VERSION 5.7 ;
BUSBITCHARS "[]" ;
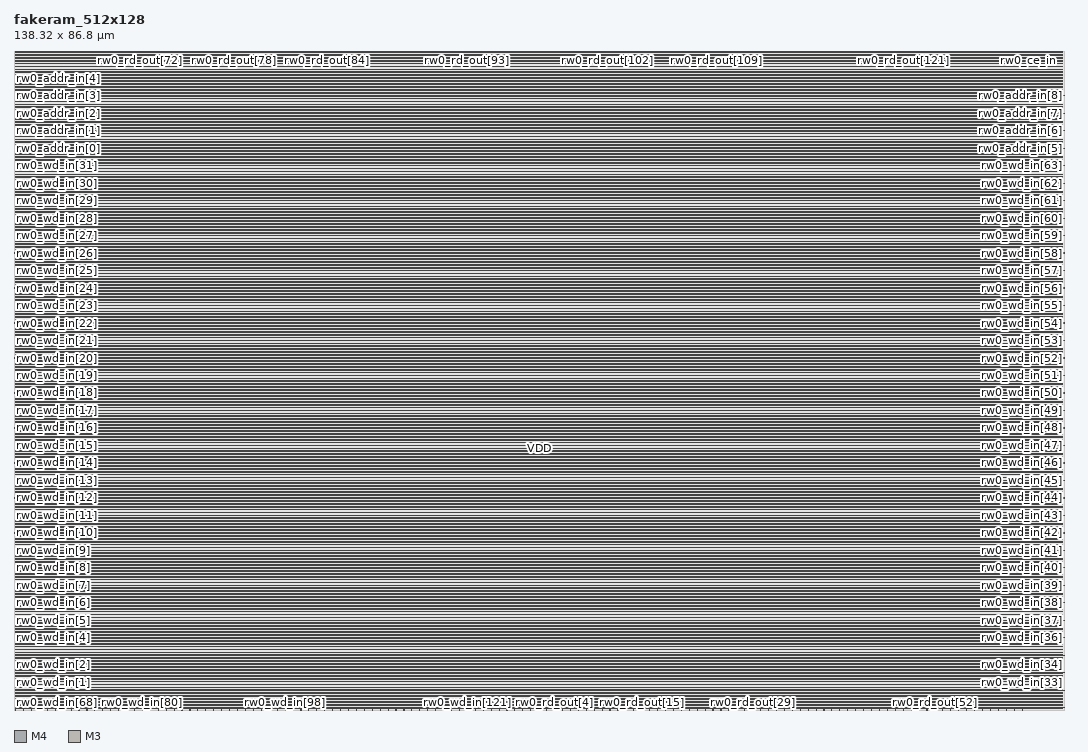
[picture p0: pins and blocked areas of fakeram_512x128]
MACRO fakeram_512x128
  FOREIGN fakeram_512x128 0 0 ;
  SYMMETRY X Y R90 ;
  SIZE 138.320 BY 86.800 ;
  CLASS BLOCK ;
  PIN rw0_wd_in[0]
    DIRECTION INPUT ;
    USE SIGNAL ;
    SHAPE ABUTMENT ;
    PORT
      LAYER M4 ;
      RECT 0.000 0.276 0.072 0.300 ;
    END
  END rw0_wd_in[0]
  PIN rw0_wd_in[1]
    DIRECTION INPUT ;
    USE SIGNAL ;
    SHAPE ABUTMENT ;
    PORT
      LAYER M4 ;
      RECT 0.000 2.580 0.072 2.604 ;
    END
  END rw0_wd_in[1]
  PIN rw0_wd_in[2]
    DIRECTION INPUT ;
    USE SIGNAL ;
    SHAPE ABUTMENT ;
    PORT
      LAYER M4 ;
      RECT 0.000 4.884 0.072 4.908 ;
    END
  END rw0_wd_in[2]
  PIN rw0_wd_in[3]
    DIRECTION INPUT ;
    USE SIGNAL ;
    SHAPE ABUTMENT ;
    PORT
      LAYER M4 ;
      RECT 0.000 7.188 0.072 7.212 ;
    END
  END rw0_wd_in[3]
  PIN rw0_wd_in[4]
    DIRECTION INPUT ;
    USE SIGNAL ;
    SHAPE ABUTMENT ;
    PORT
      LAYER M4 ;
      RECT 0.000 9.492 0.072 9.516 ;
    END
  END rw0_wd_in[4]
  PIN rw0_wd_in[5]
    DIRECTION INPUT ;
    USE SIGNAL ;
    SHAPE ABUTMENT ;
    PORT
      LAYER M4 ;
      RECT 0.000 11.796 0.072 11.820 ;
    END
  END rw0_wd_in[5]
  PIN rw0_wd_in[6]
    DIRECTION INPUT ;
    USE SIGNAL ;
    SHAPE ABUTMENT ;
    PORT
      LAYER M4 ;
      RECT 0.000 14.100 0.072 14.124 ;
    END
  END rw0_wd_in[6]
  PIN rw0_wd_in[7]
    DIRECTION INPUT ;
    USE SIGNAL ;
    SHAPE ABUTMENT ;
    PORT
      LAYER M4 ;
      RECT 0.000 16.404 0.072 16.428 ;
    END
  END rw0_wd_in[7]
  PIN rw0_wd_in[8]
    DIRECTION INPUT ;
    USE SIGNAL ;
    SHAPE ABUTMENT ;
    PORT
      LAYER M4 ;
      RECT 0.000 18.708 0.072 18.732 ;
    END
  END rw0_wd_in[8]
  PIN rw0_wd_in[9]
    DIRECTION INPUT ;
    USE SIGNAL ;
    SHAPE ABUTMENT ;
    PORT
      LAYER M4 ;
      RECT 0.000 21.012 0.072 21.036 ;
    END
  END rw0_wd_in[9]
  PIN rw0_wd_in[10]
    DIRECTION INPUT ;
    USE SIGNAL ;
    SHAPE ABUTMENT ;
    PORT
      LAYER M4 ;
      RECT 0.000 23.316 0.072 23.340 ;
    END
  END rw0_wd_in[10]
  PIN rw0_wd_in[11]
    DIRECTION INPUT ;
    USE SIGNAL ;
    SHAPE ABUTMENT ;
    PORT
      LAYER M4 ;
      RECT 0.000 25.620 0.072 25.644 ;
    END
  END rw0_wd_in[11]
  PIN rw0_wd_in[12]
    DIRECTION INPUT ;
    USE SIGNAL ;
    SHAPE ABUTMENT ;
    PORT
      LAYER M4 ;
      RECT 0.000 27.924 0.072 27.948 ;
    END
  END rw0_wd_in[12]
  PIN rw0_wd_in[13]
    DIRECTION INPUT ;
    USE SIGNAL ;
    SHAPE ABUTMENT ;
    PORT
      LAYER M4 ;
      RECT 0.000 30.228 0.072 30.252 ;
    END
  END rw0_wd_in[13]
  PIN rw0_wd_in[14]
    DIRECTION INPUT ;
    USE SIGNAL ;
    SHAPE ABUTMENT ;
    PORT
      LAYER M4 ;
      RECT 0.000 32.532 0.072 32.556 ;
    END
  END rw0_wd_in[14]
  PIN rw0_wd_in[15]
    DIRECTION INPUT ;
    USE SIGNAL ;
    SHAPE ABUTMENT ;
    PORT
      LAYER M4 ;
      RECT 0.000 34.836 0.072 34.860 ;
    END
  END rw0_wd_in[15]
  PIN rw0_wd_in[16]
    DIRECTION INPUT ;
    USE SIGNAL ;
    SHAPE ABUTMENT ;
    PORT
      LAYER M4 ;
      RECT 0.000 37.140 0.072 37.164 ;
    END
  END rw0_wd_in[16]
  PIN rw0_wd_in[17]
    DIRECTION INPUT ;
    USE SIGNAL ;
    SHAPE ABUTMENT ;
    PORT
      LAYER M4 ;
      RECT 0.000 39.444 0.072 39.468 ;
    END
  END rw0_wd_in[17]
  PIN rw0_wd_in[18]
    DIRECTION INPUT ;
    USE SIGNAL ;
    SHAPE ABUTMENT ;
    PORT
      LAYER M4 ;
      RECT 0.000 41.748 0.072 41.772 ;
    END
  END rw0_wd_in[18]
  PIN rw0_wd_in[19]
    DIRECTION INPUT ;
    USE SIGNAL ;
    SHAPE ABUTMENT ;
    PORT
      LAYER M4 ;
      RECT 0.000 44.052 0.072 44.076 ;
    END
  END rw0_wd_in[19]
  PIN rw0_wd_in[20]
    DIRECTION INPUT ;
    USE SIGNAL ;
    SHAPE ABUTMENT ;
    PORT
      LAYER M4 ;
      RECT 0.000 46.356 0.072 46.380 ;
    END
  END rw0_wd_in[20]
  PIN rw0_wd_in[21]
    DIRECTION INPUT ;
    USE SIGNAL ;
    SHAPE ABUTMENT ;
    PORT
      LAYER M4 ;
      RECT 0.000 48.660 0.072 48.684 ;
    END
  END rw0_wd_in[21]
  PIN rw0_wd_in[22]
    DIRECTION INPUT ;
    USE SIGNAL ;
    SHAPE ABUTMENT ;
    PORT
      LAYER M4 ;
      RECT 0.000 50.964 0.072 50.988 ;
    END
  END rw0_wd_in[22]
  PIN rw0_wd_in[23]
    DIRECTION INPUT ;
    USE SIGNAL ;
    SHAPE ABUTMENT ;
    PORT
      LAYER M4 ;
      RECT 0.000 53.268 0.072 53.292 ;
    END
  END rw0_wd_in[23]
  PIN rw0_wd_in[24]
    DIRECTION INPUT ;
    USE SIGNAL ;
    SHAPE ABUTMENT ;
    PORT
      LAYER M4 ;
      RECT 0.000 55.572 0.072 55.596 ;
    END
  END rw0_wd_in[24]
  PIN rw0_wd_in[25]
    DIRECTION INPUT ;
    USE SIGNAL ;
    SHAPE ABUTMENT ;
    PORT
      LAYER M4 ;
      RECT 0.000 57.876 0.072 57.900 ;
    END
  END rw0_wd_in[25]
  PIN rw0_wd_in[26]
    DIRECTION INPUT ;
    USE SIGNAL ;
    SHAPE ABUTMENT ;
    PORT
      LAYER M4 ;
      RECT 0.000 60.180 0.072 60.204 ;
    END
  END rw0_wd_in[26]
  PIN rw0_wd_in[27]
    DIRECTION INPUT ;
    USE SIGNAL ;
    SHAPE ABUTMENT ;
    PORT
      LAYER M4 ;
      RECT 0.000 62.484 0.072 62.508 ;
    END
  END rw0_wd_in[27]
  PIN rw0_wd_in[28]
    DIRECTION INPUT ;
    USE SIGNAL ;
    SHAPE ABUTMENT ;
    PORT
      LAYER M4 ;
      RECT 0.000 64.788 0.072 64.812 ;
    END
  END rw0_wd_in[28]
  PIN rw0_wd_in[29]
    DIRECTION INPUT ;
    USE SIGNAL ;
    SHAPE ABUTMENT ;
    PORT
      LAYER M4 ;
      RECT 0.000 67.092 0.072 67.116 ;
    END
  END rw0_wd_in[29]
  PIN rw0_wd_in[30]
    DIRECTION INPUT ;
    USE SIGNAL ;
    SHAPE ABUTMENT ;
    PORT
      LAYER M4 ;
      RECT 0.000 69.396 0.072 69.420 ;
    END
  END rw0_wd_in[30]
  PIN rw0_wd_in[31]
    DIRECTION INPUT ;
    USE SIGNAL ;
    SHAPE ABUTMENT ;
    PORT
      LAYER M4 ;
      RECT 0.000 71.700 0.072 71.724 ;
    END
  END rw0_wd_in[31]
  PIN rw0_wd_in[32]
    DIRECTION INPUT ;
    USE SIGNAL ;
    SHAPE ABUTMENT ;
    PORT
      LAYER M4 ;
      RECT 138.248 0.276 138.320 0.300 ;
    END
  END rw0_wd_in[32]
  PIN rw0_wd_in[33]
    DIRECTION INPUT ;
    USE SIGNAL ;
    SHAPE ABUTMENT ;
    PORT
      LAYER M4 ;
      RECT 138.248 2.580 138.320 2.604 ;
    END
  END rw0_wd_in[33]
  PIN rw0_wd_in[34]
    DIRECTION INPUT ;
    USE SIGNAL ;
    SHAPE ABUTMENT ;
    PORT
      LAYER M4 ;
      RECT 138.248 4.884 138.320 4.908 ;
    END
  END rw0_wd_in[34]
  PIN rw0_wd_in[35]
    DIRECTION INPUT ;
    USE SIGNAL ;
    SHAPE ABUTMENT ;
    PORT
      LAYER M4 ;
      RECT 138.248 7.188 138.320 7.212 ;
    END
  END rw0_wd_in[35]
  PIN rw0_wd_in[36]
    DIRECTION INPUT ;
    USE SIGNAL ;
    SHAPE ABUTMENT ;
    PORT
      LAYER M4 ;
      RECT 138.248 9.492 138.320 9.516 ;
    END
  END rw0_wd_in[36]
  PIN rw0_wd_in[37]
    DIRECTION INPUT ;
    USE SIGNAL ;
    SHAPE ABUTMENT ;
    PORT
      LAYER M4 ;
      RECT 138.248 11.796 138.320 11.820 ;
    END
  END rw0_wd_in[37]
  PIN rw0_wd_in[38]
    DIRECTION INPUT ;
    USE SIGNAL ;
    SHAPE ABUTMENT ;
    PORT
      LAYER M4 ;
      RECT 138.248 14.100 138.320 14.124 ;
    END
  END rw0_wd_in[38]
  PIN rw0_wd_in[39]
    DIRECTION INPUT ;
    USE SIGNAL ;
    SHAPE ABUTMENT ;
    PORT
      LAYER M4 ;
      RECT 138.248 16.404 138.320 16.428 ;
    END
  END rw0_wd_in[39]
  PIN rw0_wd_in[40]
    DIRECTION INPUT ;
    USE SIGNAL ;
    SHAPE ABUTMENT ;
    PORT
      LAYER M4 ;
      RECT 138.248 18.708 138.320 18.732 ;
    END
  END rw0_wd_in[40]
  PIN rw0_wd_in[41]
    DIRECTION INPUT ;
    USE SIGNAL ;
    SHAPE ABUTMENT ;
    PORT
      LAYER M4 ;
      RECT 138.248 21.012 138.320 21.036 ;
    END
  END rw0_wd_in[41]
  PIN rw0_wd_in[42]
    DIRECTION INPUT ;
    USE SIGNAL ;
    SHAPE ABUTMENT ;
    PORT
      LAYER M4 ;
      RECT 138.248 23.316 138.320 23.340 ;
    END
  END rw0_wd_in[42]
  PIN rw0_wd_in[43]
    DIRECTION INPUT ;
    USE SIGNAL ;
    SHAPE ABUTMENT ;
    PORT
      LAYER M4 ;
      RECT 138.248 25.620 138.320 25.644 ;
    END
  END rw0_wd_in[43]
  PIN rw0_wd_in[44]
    DIRECTION INPUT ;
    USE SIGNAL ;
    SHAPE ABUTMENT ;
    PORT
      LAYER M4 ;
      RECT 138.248 27.924 138.320 27.948 ;
    END
  END rw0_wd_in[44]
  PIN rw0_wd_in[45]
    DIRECTION INPUT ;
    USE SIGNAL ;
    SHAPE ABUTMENT ;
    PORT
      LAYER M4 ;
      RECT 138.248 30.228 138.320 30.252 ;
    END
  END rw0_wd_in[45]
  PIN rw0_wd_in[46]
    DIRECTION INPUT ;
    USE SIGNAL ;
    SHAPE ABUTMENT ;
    PORT
      LAYER M4 ;
      RECT 138.248 32.532 138.320 32.556 ;
    END
  END rw0_wd_in[46]
  PIN rw0_wd_in[47]
    DIRECTION INPUT ;
    USE SIGNAL ;
    SHAPE ABUTMENT ;
    PORT
      LAYER M4 ;
      RECT 138.248 34.836 138.320 34.860 ;
    END
  END rw0_wd_in[47]
  PIN rw0_wd_in[48]
    DIRECTION INPUT ;
    USE SIGNAL ;
    SHAPE ABUTMENT ;
    PORT
      LAYER M4 ;
      RECT 138.248 37.140 138.320 37.164 ;
    END
  END rw0_wd_in[48]
  PIN rw0_wd_in[49]
    DIRECTION INPUT ;
    USE SIGNAL ;
    SHAPE ABUTMENT ;
    PORT
      LAYER M4 ;
      RECT 138.248 39.444 138.320 39.468 ;
    END
  END rw0_wd_in[49]
  PIN rw0_wd_in[50]
    DIRECTION INPUT ;
    USE SIGNAL ;
    SHAPE ABUTMENT ;
    PORT
      LAYER M4 ;
      RECT 138.248 41.748 138.320 41.772 ;
    END
  END rw0_wd_in[50]
  PIN rw0_wd_in[51]
    DIRECTION INPUT ;
    USE SIGNAL ;
    SHAPE ABUTMENT ;
    PORT
      LAYER M4 ;
      RECT 138.248 44.052 138.320 44.076 ;
    END
  END rw0_wd_in[51]
  PIN rw0_wd_in[52]
    DIRECTION INPUT ;
    USE SIGNAL ;
    SHAPE ABUTMENT ;
    PORT
      LAYER M4 ;
      RECT 138.248 46.356 138.320 46.380 ;
    END
  END rw0_wd_in[52]
  PIN rw0_wd_in[53]
    DIRECTION INPUT ;
    USE SIGNAL ;
    SHAPE ABUTMENT ;
    PORT
      LAYER M4 ;
      RECT 138.248 48.660 138.320 48.684 ;
    END
  END rw0_wd_in[53]
  PIN rw0_wd_in[54]
    DIRECTION INPUT ;
    USE SIGNAL ;
    SHAPE ABUTMENT ;
    PORT
      LAYER M4 ;
      RECT 138.248 50.964 138.320 50.988 ;
    END
  END rw0_wd_in[54]
  PIN rw0_wd_in[55]
    DIRECTION INPUT ;
    USE SIGNAL ;
    SHAPE ABUTMENT ;
    PORT
      LAYER M4 ;
      RECT 138.248 53.268 138.320 53.292 ;
    END
  END rw0_wd_in[55]
  PIN rw0_wd_in[56]
    DIRECTION INPUT ;
    USE SIGNAL ;
    SHAPE ABUTMENT ;
    PORT
      LAYER M4 ;
      RECT 138.248 55.572 138.320 55.596 ;
    END
  END rw0_wd_in[56]
  PIN rw0_wd_in[57]
    DIRECTION INPUT ;
    USE SIGNAL ;
    SHAPE ABUTMENT ;
    PORT
      LAYER M4 ;
      RECT 138.248 57.876 138.320 57.900 ;
    END
  END rw0_wd_in[57]
  PIN rw0_wd_in[58]
    DIRECTION INPUT ;
    USE SIGNAL ;
    SHAPE ABUTMENT ;
    PORT
      LAYER M4 ;
      RECT 138.248 60.180 138.320 60.204 ;
    END
  END rw0_wd_in[58]
  PIN rw0_wd_in[59]
    DIRECTION INPUT ;
    USE SIGNAL ;
    SHAPE ABUTMENT ;
    PORT
      LAYER M4 ;
      RECT 138.248 62.484 138.320 62.508 ;
    END
  END rw0_wd_in[59]
  PIN rw0_wd_in[60]
    DIRECTION INPUT ;
    USE SIGNAL ;
    SHAPE ABUTMENT ;
    PORT
      LAYER M4 ;
      RECT 138.248 64.788 138.320 64.812 ;
    END
  END rw0_wd_in[60]
  PIN rw0_wd_in[61]
    DIRECTION INPUT ;
    USE SIGNAL ;
    SHAPE ABUTMENT ;
    PORT
      LAYER M4 ;
      RECT 138.248 67.092 138.320 67.116 ;
    END
  END rw0_wd_in[61]
  PIN rw0_wd_in[62]
    DIRECTION INPUT ;
    USE SIGNAL ;
    SHAPE ABUTMENT ;
    PORT
      LAYER M4 ;
      RECT 138.248 69.396 138.320 69.420 ;
    END
  END rw0_wd_in[62]
  PIN rw0_wd_in[63]
    DIRECTION INPUT ;
    USE SIGNAL ;
    SHAPE ABUTMENT ;
    PORT
      LAYER M4 ;
      RECT 138.248 71.700 138.320 71.724 ;
    END
  END rw0_wd_in[63]
  PIN rw0_wd_in[64]
    DIRECTION INPUT ;
    USE SIGNAL ;
    SHAPE ABUTMENT ;
    PORT
      LAYER M3 ;
      RECT 0.207 0.000 0.225 0.054 ;
    END
  END rw0_wd_in[64]
  PIN rw0_wd_in[65]
    DIRECTION INPUT ;
    USE SIGNAL ;
    SHAPE ABUTMENT ;
    PORT
      LAYER M3 ;
      RECT 1.251 0.000 1.269 0.054 ;
    END
  END rw0_wd_in[65]
  PIN rw0_wd_in[66]
    DIRECTION INPUT ;
    USE SIGNAL ;
    SHAPE ABUTMENT ;
    PORT
      LAYER M3 ;
      RECT 2.295 0.000 2.313 0.054 ;
    END
  END rw0_wd_in[66]
  PIN rw0_wd_in[67]
    DIRECTION INPUT ;
    USE SIGNAL ;
    SHAPE ABUTMENT ;
    PORT
      LAYER M3 ;
      RECT 3.339 0.000 3.357 0.054 ;
    END
  END rw0_wd_in[67]
  PIN rw0_wd_in[68]
    DIRECTION INPUT ;
    USE SIGNAL ;
    SHAPE ABUTMENT ;
    PORT
      LAYER M3 ;
      RECT 4.383 0.000 4.401 0.054 ;
    END
  END rw0_wd_in[68]
  PIN rw0_wd_in[69]
    DIRECTION INPUT ;
    USE SIGNAL ;
    SHAPE ABUTMENT ;
    PORT
      LAYER M3 ;
      RECT 5.427 0.000 5.445 0.054 ;
    END
  END rw0_wd_in[69]
  PIN rw0_wd_in[70]
    DIRECTION INPUT ;
    USE SIGNAL ;
    SHAPE ABUTMENT ;
    PORT
      LAYER M3 ;
      RECT 6.471 0.000 6.489 0.054 ;
    END
  END rw0_wd_in[70]
  PIN rw0_wd_in[71]
    DIRECTION INPUT ;
    USE SIGNAL ;
    SHAPE ABUTMENT ;
    PORT
      LAYER M3 ;
      RECT 7.515 0.000 7.533 0.054 ;
    END
  END rw0_wd_in[71]
  PIN rw0_wd_in[72]
    DIRECTION INPUT ;
    USE SIGNAL ;
    SHAPE ABUTMENT ;
    PORT
      LAYER M3 ;
      RECT 8.559 0.000 8.577 0.054 ;
    END
  END rw0_wd_in[72]
  PIN rw0_wd_in[73]
    DIRECTION INPUT ;
    USE SIGNAL ;
    SHAPE ABUTMENT ;
    PORT
      LAYER M3 ;
      RECT 9.603 0.000 9.621 0.054 ;
    END
  END rw0_wd_in[73]
  PIN rw0_wd_in[74]
    DIRECTION INPUT ;
    USE SIGNAL ;
    SHAPE ABUTMENT ;
    PORT
      LAYER M3 ;
      RECT 10.647 0.000 10.665 0.054 ;
    END
  END rw0_wd_in[74]
  PIN rw0_wd_in[75]
    DIRECTION INPUT ;
    USE SIGNAL ;
    SHAPE ABUTMENT ;
    PORT
      LAYER M3 ;
      RECT 11.691 0.000 11.709 0.054 ;
    END
  END rw0_wd_in[75]
  PIN rw0_wd_in[76]
    DIRECTION INPUT ;
    USE SIGNAL ;
    SHAPE ABUTMENT ;
    PORT
      LAYER M3 ;
      RECT 12.735 0.000 12.753 0.054 ;
    END
  END rw0_wd_in[76]
  PIN rw0_wd_in[77]
    DIRECTION INPUT ;
    USE SIGNAL ;
    SHAPE ABUTMENT ;
    PORT
      LAYER M3 ;
      RECT 13.779 0.000 13.797 0.054 ;
    END
  END rw0_wd_in[77]
  PIN rw0_wd_in[78]
    DIRECTION INPUT ;
    USE SIGNAL ;
    SHAPE ABUTMENT ;
    PORT
      LAYER M3 ;
      RECT 14.823 0.000 14.841 0.054 ;
    END
  END rw0_wd_in[78]
  PIN rw0_wd_in[79]
    DIRECTION INPUT ;
    USE SIGNAL ;
    SHAPE ABUTMENT ;
    PORT
      LAYER M3 ;
      RECT 15.867 0.000 15.885 0.054 ;
    END
  END rw0_wd_in[79]
  PIN rw0_wd_in[80]
    DIRECTION INPUT ;
    USE SIGNAL ;
    SHAPE ABUTMENT ;
    PORT
      LAYER M3 ;
      RECT 16.911 0.000 16.929 0.054 ;
    END
  END rw0_wd_in[80]
  PIN rw0_wd_in[81]
    DIRECTION INPUT ;
    USE SIGNAL ;
    SHAPE ABUTMENT ;
    PORT
      LAYER M3 ;
      RECT 17.955 0.000 17.973 0.054 ;
    END
  END rw0_wd_in[81]
  PIN rw0_wd_in[82]
    DIRECTION INPUT ;
    USE SIGNAL ;
    SHAPE ABUTMENT ;
    PORT
      LAYER M3 ;
      RECT 18.999 0.000 19.017 0.054 ;
    END
  END rw0_wd_in[82]
  PIN rw0_wd_in[83]
    DIRECTION INPUT ;
    USE SIGNAL ;
    SHAPE ABUTMENT ;
    PORT
      LAYER M3 ;
      RECT 20.043 0.000 20.061 0.054 ;
    END
  END rw0_wd_in[83]
  PIN rw0_wd_in[84]
    DIRECTION INPUT ;
    USE SIGNAL ;
    SHAPE ABUTMENT ;
    PORT
      LAYER M3 ;
      RECT 21.087 0.000 21.105 0.054 ;
    END
  END rw0_wd_in[84]
  PIN rw0_wd_in[85]
    DIRECTION INPUT ;
    USE SIGNAL ;
    SHAPE ABUTMENT ;
    PORT
      LAYER M3 ;
      RECT 22.131 0.000 22.149 0.054 ;
    END
  END rw0_wd_in[85]
  PIN rw0_wd_in[86]
    DIRECTION INPUT ;
    USE SIGNAL ;
    SHAPE ABUTMENT ;
    PORT
      LAYER M3 ;
      RECT 23.175 0.000 23.193 0.054 ;
    END
  END rw0_wd_in[86]
  PIN rw0_wd_in[87]
    DIRECTION INPUT ;
    USE SIGNAL ;
    SHAPE ABUTMENT ;
    PORT
      LAYER M3 ;
      RECT 24.219 0.000 24.237 0.054 ;
    END
  END rw0_wd_in[87]
  PIN rw0_wd_in[88]
    DIRECTION INPUT ;
    USE SIGNAL ;
    SHAPE ABUTMENT ;
    PORT
      LAYER M3 ;
      RECT 25.263 0.000 25.281 0.054 ;
    END
  END rw0_wd_in[88]
  PIN rw0_wd_in[89]
    DIRECTION INPUT ;
    USE SIGNAL ;
    SHAPE ABUTMENT ;
    PORT
      LAYER M3 ;
      RECT 26.307 0.000 26.325 0.054 ;
    END
  END rw0_wd_in[89]
  PIN rw0_wd_in[90]
    DIRECTION INPUT ;
    USE SIGNAL ;
    SHAPE ABUTMENT ;
    PORT
      LAYER M3 ;
      RECT 27.351 0.000 27.369 0.054 ;
    END
  END rw0_wd_in[90]
  PIN rw0_wd_in[91]
    DIRECTION INPUT ;
    USE SIGNAL ;
    SHAPE ABUTMENT ;
    PORT
      LAYER M3 ;
      RECT 28.395 0.000 28.413 0.054 ;
    END
  END rw0_wd_in[91]
  PIN rw0_wd_in[92]
    DIRECTION INPUT ;
    USE SIGNAL ;
    SHAPE ABUTMENT ;
    PORT
      LAYER M3 ;
      RECT 29.439 0.000 29.457 0.054 ;
    END
  END rw0_wd_in[92]
  PIN rw0_wd_in[93]
    DIRECTION INPUT ;
    USE SIGNAL ;
    SHAPE ABUTMENT ;
    PORT
      LAYER M3 ;
      RECT 30.483 0.000 30.501 0.054 ;
    END
  END rw0_wd_in[93]
  PIN rw0_wd_in[94]
    DIRECTION INPUT ;
    USE SIGNAL ;
    SHAPE ABUTMENT ;
    PORT
      LAYER M3 ;
      RECT 31.527 0.000 31.545 0.054 ;
    END
  END rw0_wd_in[94]
  PIN rw0_wd_in[95]
    DIRECTION INPUT ;
    USE SIGNAL ;
    SHAPE ABUTMENT ;
    PORT
      LAYER M3 ;
      RECT 32.571 0.000 32.589 0.054 ;
    END
  END rw0_wd_in[95]
  PIN rw0_wd_in[96]
    DIRECTION INPUT ;
    USE SIGNAL ;
    SHAPE ABUTMENT ;
    PORT
      LAYER M3 ;
      RECT 33.615 0.000 33.633 0.054 ;
    END
  END rw0_wd_in[96]
  PIN rw0_wd_in[97]
    DIRECTION INPUT ;
    USE SIGNAL ;
    SHAPE ABUTMENT ;
    PORT
      LAYER M3 ;
      RECT 34.659 0.000 34.677 0.054 ;
    END
  END rw0_wd_in[97]
  PIN rw0_wd_in[98]
    DIRECTION INPUT ;
    USE SIGNAL ;
    SHAPE ABUTMENT ;
    PORT
      LAYER M3 ;
      RECT 35.703 0.000 35.721 0.054 ;
    END
  END rw0_wd_in[98]
  PIN rw0_wd_in[99]
    DIRECTION INPUT ;
    USE SIGNAL ;
    SHAPE ABUTMENT ;
    PORT
      LAYER M3 ;
      RECT 36.747 0.000 36.765 0.054 ;
    END
  END rw0_wd_in[99]
  PIN rw0_wd_in[100]
    DIRECTION INPUT ;
    USE SIGNAL ;
    SHAPE ABUTMENT ;
    PORT
      LAYER M3 ;
      RECT 37.791 0.000 37.809 0.054 ;
    END
  END rw0_wd_in[100]
  PIN rw0_wd_in[101]
    DIRECTION INPUT ;
    USE SIGNAL ;
    SHAPE ABUTMENT ;
    PORT
      LAYER M3 ;
      RECT 38.835 0.000 38.853 0.054 ;
    END
  END rw0_wd_in[101]
  PIN rw0_wd_in[102]
    DIRECTION INPUT ;
    USE SIGNAL ;
    SHAPE ABUTMENT ;
    PORT
      LAYER M3 ;
      RECT 39.879 0.000 39.897 0.054 ;
    END
  END rw0_wd_in[102]
  PIN rw0_wd_in[103]
    DIRECTION INPUT ;
    USE SIGNAL ;
    SHAPE ABUTMENT ;
    PORT
      LAYER M3 ;
      RECT 40.923 0.000 40.941 0.054 ;
    END
  END rw0_wd_in[103]
  PIN rw0_wd_in[104]
    DIRECTION INPUT ;
    USE SIGNAL ;
    SHAPE ABUTMENT ;
    PORT
      LAYER M3 ;
      RECT 41.967 0.000 41.985 0.054 ;
    END
  END rw0_wd_in[104]
  PIN rw0_wd_in[105]
    DIRECTION INPUT ;
    USE SIGNAL ;
    SHAPE ABUTMENT ;
    PORT
      LAYER M3 ;
      RECT 43.011 0.000 43.029 0.054 ;
    END
  END rw0_wd_in[105]
  PIN rw0_wd_in[106]
    DIRECTION INPUT ;
    USE SIGNAL ;
    SHAPE ABUTMENT ;
    PORT
      LAYER M3 ;
      RECT 44.055 0.000 44.073 0.054 ;
    END
  END rw0_wd_in[106]
  PIN rw0_wd_in[107]
    DIRECTION INPUT ;
    USE SIGNAL ;
    SHAPE ABUTMENT ;
    PORT
      LAYER M3 ;
      RECT 45.099 0.000 45.117 0.054 ;
    END
  END rw0_wd_in[107]
  PIN rw0_wd_in[108]
    DIRECTION INPUT ;
    USE SIGNAL ;
    SHAPE ABUTMENT ;
    PORT
      LAYER M3 ;
      RECT 46.143 0.000 46.161 0.054 ;
    END
  END rw0_wd_in[108]
  PIN rw0_wd_in[109]
    DIRECTION INPUT ;
    USE SIGNAL ;
    SHAPE ABUTMENT ;
    PORT
      LAYER M3 ;
      RECT 47.187 0.000 47.205 0.054 ;
    END
  END rw0_wd_in[109]
  PIN rw0_wd_in[110]
    DIRECTION INPUT ;
    USE SIGNAL ;
    SHAPE ABUTMENT ;
    PORT
      LAYER M3 ;
      RECT 48.231 0.000 48.249 0.054 ;
    END
  END rw0_wd_in[110]
  PIN rw0_wd_in[111]
    DIRECTION INPUT ;
    USE SIGNAL ;
    SHAPE ABUTMENT ;
    PORT
      LAYER M3 ;
      RECT 49.275 0.000 49.293 0.054 ;
    END
  END rw0_wd_in[111]
  PIN rw0_wd_in[112]
    DIRECTION INPUT ;
    USE SIGNAL ;
    SHAPE ABUTMENT ;
    PORT
      LAYER M3 ;
      RECT 50.319 0.000 50.337 0.054 ;
    END
  END rw0_wd_in[112]
  PIN rw0_wd_in[113]
    DIRECTION INPUT ;
    USE SIGNAL ;
    SHAPE ABUTMENT ;
    PORT
      LAYER M3 ;
      RECT 51.363 0.000 51.381 0.054 ;
    END
  END rw0_wd_in[113]
  PIN rw0_wd_in[114]
    DIRECTION INPUT ;
    USE SIGNAL ;
    SHAPE ABUTMENT ;
    PORT
      LAYER M3 ;
      RECT 52.407 0.000 52.425 0.054 ;
    END
  END rw0_wd_in[114]
  PIN rw0_wd_in[115]
    DIRECTION INPUT ;
    USE SIGNAL ;
    SHAPE ABUTMENT ;
    PORT
      LAYER M3 ;
      RECT 53.451 0.000 53.469 0.054 ;
    END
  END rw0_wd_in[115]
  PIN rw0_wd_in[116]
    DIRECTION INPUT ;
    USE SIGNAL ;
    SHAPE ABUTMENT ;
    PORT
      LAYER M3 ;
      RECT 54.495 0.000 54.513 0.054 ;
    END
  END rw0_wd_in[116]
  PIN rw0_wd_in[117]
    DIRECTION INPUT ;
    USE SIGNAL ;
    SHAPE ABUTMENT ;
    PORT
      LAYER M3 ;
      RECT 55.539 0.000 55.557 0.054 ;
    END
  END rw0_wd_in[117]
  PIN rw0_wd_in[118]
    DIRECTION INPUT ;
    USE SIGNAL ;
    SHAPE ABUTMENT ;
    PORT
      LAYER M3 ;
      RECT 56.583 0.000 56.601 0.054 ;
    END
  END rw0_wd_in[118]
  PIN rw0_wd_in[119]
    DIRECTION INPUT ;
    USE SIGNAL ;
    SHAPE ABUTMENT ;
    PORT
      LAYER M3 ;
      RECT 57.627 0.000 57.645 0.054 ;
    END
  END rw0_wd_in[119]
  PIN rw0_wd_in[120]
    DIRECTION INPUT ;
    USE SIGNAL ;
    SHAPE ABUTMENT ;
    PORT
      LAYER M3 ;
      RECT 58.671 0.000 58.689 0.054 ;
    END
  END rw0_wd_in[120]
  PIN rw0_wd_in[121]
    DIRECTION INPUT ;
    USE SIGNAL ;
    SHAPE ABUTMENT ;
    PORT
      LAYER M3 ;
      RECT 59.715 0.000 59.733 0.054 ;
    END
  END rw0_wd_in[121]
  PIN rw0_wd_in[122]
    DIRECTION INPUT ;
    USE SIGNAL ;
    SHAPE ABUTMENT ;
    PORT
      LAYER M3 ;
      RECT 60.759 0.000 60.777 0.054 ;
    END
  END rw0_wd_in[122]
  PIN rw0_wd_in[123]
    DIRECTION INPUT ;
    USE SIGNAL ;
    SHAPE ABUTMENT ;
    PORT
      LAYER M3 ;
      RECT 61.803 0.000 61.821 0.054 ;
    END
  END rw0_wd_in[123]
  PIN rw0_wd_in[124]
    DIRECTION INPUT ;
    USE SIGNAL ;
    SHAPE ABUTMENT ;
    PORT
      LAYER M3 ;
      RECT 62.847 0.000 62.865 0.054 ;
    END
  END rw0_wd_in[124]
  PIN rw0_wd_in[125]
    DIRECTION INPUT ;
    USE SIGNAL ;
    SHAPE ABUTMENT ;
    PORT
      LAYER M3 ;
      RECT 63.891 0.000 63.909 0.054 ;
    END
  END rw0_wd_in[125]
  PIN rw0_wd_in[126]
    DIRECTION INPUT ;
    USE SIGNAL ;
    SHAPE ABUTMENT ;
    PORT
      LAYER M3 ;
      RECT 64.935 0.000 64.953 0.054 ;
    END
  END rw0_wd_in[126]
  PIN rw0_wd_in[127]
    DIRECTION INPUT ;
    USE SIGNAL ;
    SHAPE ABUTMENT ;
    PORT
      LAYER M3 ;
      RECT 65.979 0.000 65.997 0.054 ;
    END
  END rw0_wd_in[127]
  PIN rw0_rd_out[0]
    DIRECTION OUTPUT ;
    USE SIGNAL ;
    SHAPE ABUTMENT ;
    PORT
      LAYER M3 ;
      RECT 67.023 0.000 67.041 0.054 ;
    END
  END rw0_rd_out[0]
  PIN rw0_rd_out[1]
    DIRECTION OUTPUT ;
    USE SIGNAL ;
    SHAPE ABUTMENT ;
    PORT
      LAYER M3 ;
      RECT 68.067 0.000 68.085 0.054 ;
    END
  END rw0_rd_out[1]
  PIN rw0_rd_out[2]
    DIRECTION OUTPUT ;
    USE SIGNAL ;
    SHAPE ABUTMENT ;
    PORT
      LAYER M3 ;
      RECT 69.111 0.000 69.129 0.054 ;
    END
  END rw0_rd_out[2]
  PIN rw0_rd_out[3]
    DIRECTION OUTPUT ;
    USE SIGNAL ;
    SHAPE ABUTMENT ;
    PORT
      LAYER M3 ;
      RECT 70.155 0.000 70.173 0.054 ;
    END
  END rw0_rd_out[3]
  PIN rw0_rd_out[4]
    DIRECTION OUTPUT ;
    USE SIGNAL ;
    SHAPE ABUTMENT ;
    PORT
      LAYER M3 ;
      RECT 71.199 0.000 71.217 0.054 ;
    END
  END rw0_rd_out[4]
  PIN rw0_rd_out[5]
    DIRECTION OUTPUT ;
    USE SIGNAL ;
    SHAPE ABUTMENT ;
    PORT
      LAYER M3 ;
      RECT 72.243 0.000 72.261 0.054 ;
    END
  END rw0_rd_out[5]
  PIN rw0_rd_out[6]
    DIRECTION OUTPUT ;
    USE SIGNAL ;
    SHAPE ABUTMENT ;
    PORT
      LAYER M3 ;
      RECT 73.287 0.000 73.305 0.054 ;
    END
  END rw0_rd_out[6]
  PIN rw0_rd_out[7]
    DIRECTION OUTPUT ;
    USE SIGNAL ;
    SHAPE ABUTMENT ;
    PORT
      LAYER M3 ;
      RECT 74.331 0.000 74.349 0.054 ;
    END
  END rw0_rd_out[7]
  PIN rw0_rd_out[8]
    DIRECTION OUTPUT ;
    USE SIGNAL ;
    SHAPE ABUTMENT ;
    PORT
      LAYER M3 ;
      RECT 75.375 0.000 75.393 0.054 ;
    END
  END rw0_rd_out[8]
  PIN rw0_rd_out[9]
    DIRECTION OUTPUT ;
    USE SIGNAL ;
    SHAPE ABUTMENT ;
    PORT
      LAYER M3 ;
      RECT 76.419 0.000 76.437 0.054 ;
    END
  END rw0_rd_out[9]
  PIN rw0_rd_out[10]
    DIRECTION OUTPUT ;
    USE SIGNAL ;
    SHAPE ABUTMENT ;
    PORT
      LAYER M3 ;
      RECT 77.463 0.000 77.481 0.054 ;
    END
  END rw0_rd_out[10]
  PIN rw0_rd_out[11]
    DIRECTION OUTPUT ;
    USE SIGNAL ;
    SHAPE ABUTMENT ;
    PORT
      LAYER M3 ;
      RECT 78.507 0.000 78.525 0.054 ;
    END
  END rw0_rd_out[11]
  PIN rw0_rd_out[12]
    DIRECTION OUTPUT ;
    USE SIGNAL ;
    SHAPE ABUTMENT ;
    PORT
      LAYER M3 ;
      RECT 79.551 0.000 79.569 0.054 ;
    END
  END rw0_rd_out[12]
  PIN rw0_rd_out[13]
    DIRECTION OUTPUT ;
    USE SIGNAL ;
    SHAPE ABUTMENT ;
    PORT
      LAYER M3 ;
      RECT 80.595 0.000 80.613 0.054 ;
    END
  END rw0_rd_out[13]
  PIN rw0_rd_out[14]
    DIRECTION OUTPUT ;
    USE SIGNAL ;
    SHAPE ABUTMENT ;
    PORT
      LAYER M3 ;
      RECT 81.639 0.000 81.657 0.054 ;
    END
  END rw0_rd_out[14]
  PIN rw0_rd_out[15]
    DIRECTION OUTPUT ;
    USE SIGNAL ;
    SHAPE ABUTMENT ;
    PORT
      LAYER M3 ;
      RECT 82.683 0.000 82.701 0.054 ;
    END
  END rw0_rd_out[15]
  PIN rw0_rd_out[16]
    DIRECTION OUTPUT ;
    USE SIGNAL ;
    SHAPE ABUTMENT ;
    PORT
      LAYER M3 ;
      RECT 83.727 0.000 83.745 0.054 ;
    END
  END rw0_rd_out[16]
  PIN rw0_rd_out[17]
    DIRECTION OUTPUT ;
    USE SIGNAL ;
    SHAPE ABUTMENT ;
    PORT
      LAYER M3 ;
      RECT 84.771 0.000 84.789 0.054 ;
    END
  END rw0_rd_out[17]
  PIN rw0_rd_out[18]
    DIRECTION OUTPUT ;
    USE SIGNAL ;
    SHAPE ABUTMENT ;
    PORT
      LAYER M3 ;
      RECT 85.815 0.000 85.833 0.054 ;
    END
  END rw0_rd_out[18]
  PIN rw0_rd_out[19]
    DIRECTION OUTPUT ;
    USE SIGNAL ;
    SHAPE ABUTMENT ;
    PORT
      LAYER M3 ;
      RECT 86.859 0.000 86.877 0.054 ;
    END
  END rw0_rd_out[19]
  PIN rw0_rd_out[20]
    DIRECTION OUTPUT ;
    USE SIGNAL ;
    SHAPE ABUTMENT ;
    PORT
      LAYER M3 ;
      RECT 87.903 0.000 87.921 0.054 ;
    END
  END rw0_rd_out[20]
  PIN rw0_rd_out[21]
    DIRECTION OUTPUT ;
    USE SIGNAL ;
    SHAPE ABUTMENT ;
    PORT
      LAYER M3 ;
      RECT 88.947 0.000 88.965 0.054 ;
    END
  END rw0_rd_out[21]
  PIN rw0_rd_out[22]
    DIRECTION OUTPUT ;
    USE SIGNAL ;
    SHAPE ABUTMENT ;
    PORT
      LAYER M3 ;
      RECT 89.991 0.000 90.009 0.054 ;
    END
  END rw0_rd_out[22]
  PIN rw0_rd_out[23]
    DIRECTION OUTPUT ;
    USE SIGNAL ;
    SHAPE ABUTMENT ;
    PORT
      LAYER M3 ;
      RECT 91.035 0.000 91.053 0.054 ;
    END
  END rw0_rd_out[23]
  PIN rw0_rd_out[24]
    DIRECTION OUTPUT ;
    USE SIGNAL ;
    SHAPE ABUTMENT ;
    PORT
      LAYER M3 ;
      RECT 92.079 0.000 92.097 0.054 ;
    END
  END rw0_rd_out[24]
  PIN rw0_rd_out[25]
    DIRECTION OUTPUT ;
    USE SIGNAL ;
    SHAPE ABUTMENT ;
    PORT
      LAYER M3 ;
      RECT 93.123 0.000 93.141 0.054 ;
    END
  END rw0_rd_out[25]
  PIN rw0_rd_out[26]
    DIRECTION OUTPUT ;
    USE SIGNAL ;
    SHAPE ABUTMENT ;
    PORT
      LAYER M3 ;
      RECT 94.167 0.000 94.185 0.054 ;
    END
  END rw0_rd_out[26]
  PIN rw0_rd_out[27]
    DIRECTION OUTPUT ;
    USE SIGNAL ;
    SHAPE ABUTMENT ;
    PORT
      LAYER M3 ;
      RECT 95.211 0.000 95.229 0.054 ;
    END
  END rw0_rd_out[27]
  PIN rw0_rd_out[28]
    DIRECTION OUTPUT ;
    USE SIGNAL ;
    SHAPE ABUTMENT ;
    PORT
      LAYER M3 ;
      RECT 96.255 0.000 96.273 0.054 ;
    END
  END rw0_rd_out[28]
  PIN rw0_rd_out[29]
    DIRECTION OUTPUT ;
    USE SIGNAL ;
    SHAPE ABUTMENT ;
    PORT
      LAYER M3 ;
      RECT 97.299 0.000 97.317 0.054 ;
    END
  END rw0_rd_out[29]
  PIN rw0_rd_out[30]
    DIRECTION OUTPUT ;
    USE SIGNAL ;
    SHAPE ABUTMENT ;
    PORT
      LAYER M3 ;
      RECT 98.343 0.000 98.361 0.054 ;
    END
  END rw0_rd_out[30]
  PIN rw0_rd_out[31]
    DIRECTION OUTPUT ;
    USE SIGNAL ;
    SHAPE ABUTMENT ;
    PORT
      LAYER M3 ;
      RECT 99.387 0.000 99.405 0.054 ;
    END
  END rw0_rd_out[31]
  PIN rw0_rd_out[32]
    DIRECTION OUTPUT ;
    USE SIGNAL ;
    SHAPE ABUTMENT ;
    PORT
      LAYER M3 ;
      RECT 100.431 0.000 100.449 0.054 ;
    END
  END rw0_rd_out[32]
  PIN rw0_rd_out[33]
    DIRECTION OUTPUT ;
    USE SIGNAL ;
    SHAPE ABUTMENT ;
    PORT
      LAYER M3 ;
      RECT 101.475 0.000 101.493 0.054 ;
    END
  END rw0_rd_out[33]
  PIN rw0_rd_out[34]
    DIRECTION OUTPUT ;
    USE SIGNAL ;
    SHAPE ABUTMENT ;
    PORT
      LAYER M3 ;
      RECT 102.519 0.000 102.537 0.054 ;
    END
  END rw0_rd_out[34]
  PIN rw0_rd_out[35]
    DIRECTION OUTPUT ;
    USE SIGNAL ;
    SHAPE ABUTMENT ;
    PORT
      LAYER M3 ;
      RECT 103.563 0.000 103.581 0.054 ;
    END
  END rw0_rd_out[35]
  PIN rw0_rd_out[36]
    DIRECTION OUTPUT ;
    USE SIGNAL ;
    SHAPE ABUTMENT ;
    PORT
      LAYER M3 ;
      RECT 104.607 0.000 104.625 0.054 ;
    END
  END rw0_rd_out[36]
  PIN rw0_rd_out[37]
    DIRECTION OUTPUT ;
    USE SIGNAL ;
    SHAPE ABUTMENT ;
    PORT
      LAYER M3 ;
      RECT 105.651 0.000 105.669 0.054 ;
    END
  END rw0_rd_out[37]
  PIN rw0_rd_out[38]
    DIRECTION OUTPUT ;
    USE SIGNAL ;
    SHAPE ABUTMENT ;
    PORT
      LAYER M3 ;
      RECT 106.695 0.000 106.713 0.054 ;
    END
  END rw0_rd_out[38]
  PIN rw0_rd_out[39]
    DIRECTION OUTPUT ;
    USE SIGNAL ;
    SHAPE ABUTMENT ;
    PORT
      LAYER M3 ;
      RECT 107.739 0.000 107.757 0.054 ;
    END
  END rw0_rd_out[39]
  PIN rw0_rd_out[40]
    DIRECTION OUTPUT ;
    USE SIGNAL ;
    SHAPE ABUTMENT ;
    PORT
      LAYER M3 ;
      RECT 108.783 0.000 108.801 0.054 ;
    END
  END rw0_rd_out[40]
  PIN rw0_rd_out[41]
    DIRECTION OUTPUT ;
    USE SIGNAL ;
    SHAPE ABUTMENT ;
    PORT
      LAYER M3 ;
      RECT 109.827 0.000 109.845 0.054 ;
    END
  END rw0_rd_out[41]
  PIN rw0_rd_out[42]
    DIRECTION OUTPUT ;
    USE SIGNAL ;
    SHAPE ABUTMENT ;
    PORT
      LAYER M3 ;
      RECT 110.871 0.000 110.889 0.054 ;
    END
  END rw0_rd_out[42]
  PIN rw0_rd_out[43]
    DIRECTION OUTPUT ;
    USE SIGNAL ;
    SHAPE ABUTMENT ;
    PORT
      LAYER M3 ;
      RECT 111.915 0.000 111.933 0.054 ;
    END
  END rw0_rd_out[43]
  PIN rw0_rd_out[44]
    DIRECTION OUTPUT ;
    USE SIGNAL ;
    SHAPE ABUTMENT ;
    PORT
      LAYER M3 ;
      RECT 112.959 0.000 112.977 0.054 ;
    END
  END rw0_rd_out[44]
  PIN rw0_rd_out[45]
    DIRECTION OUTPUT ;
    USE SIGNAL ;
    SHAPE ABUTMENT ;
    PORT
      LAYER M3 ;
      RECT 114.003 0.000 114.021 0.054 ;
    END
  END rw0_rd_out[45]
  PIN rw0_rd_out[46]
    DIRECTION OUTPUT ;
    USE SIGNAL ;
    SHAPE ABUTMENT ;
    PORT
      LAYER M3 ;
      RECT 115.047 0.000 115.065 0.054 ;
    END
  END rw0_rd_out[46]
  PIN rw0_rd_out[47]
    DIRECTION OUTPUT ;
    USE SIGNAL ;
    SHAPE ABUTMENT ;
    PORT
      LAYER M3 ;
      RECT 116.091 0.000 116.109 0.054 ;
    END
  END rw0_rd_out[47]
  PIN rw0_rd_out[48]
    DIRECTION OUTPUT ;
    USE SIGNAL ;
    SHAPE ABUTMENT ;
    PORT
      LAYER M3 ;
      RECT 117.135 0.000 117.153 0.054 ;
    END
  END rw0_rd_out[48]
  PIN rw0_rd_out[49]
    DIRECTION OUTPUT ;
    USE SIGNAL ;
    SHAPE ABUTMENT ;
    PORT
      LAYER M3 ;
      RECT 118.179 0.000 118.197 0.054 ;
    END
  END rw0_rd_out[49]
  PIN rw0_rd_out[50]
    DIRECTION OUTPUT ;
    USE SIGNAL ;
    SHAPE ABUTMENT ;
    PORT
      LAYER M3 ;
      RECT 119.223 0.000 119.241 0.054 ;
    END
  END rw0_rd_out[50]
  PIN rw0_rd_out[51]
    DIRECTION OUTPUT ;
    USE SIGNAL ;
    SHAPE ABUTMENT ;
    PORT
      LAYER M3 ;
      RECT 120.267 0.000 120.285 0.054 ;
    END
  END rw0_rd_out[51]
  PIN rw0_rd_out[52]
    DIRECTION OUTPUT ;
    USE SIGNAL ;
    SHAPE ABUTMENT ;
    PORT
      LAYER M3 ;
      RECT 121.311 0.000 121.329 0.054 ;
    END
  END rw0_rd_out[52]
  PIN rw0_rd_out[53]
    DIRECTION OUTPUT ;
    USE SIGNAL ;
    SHAPE ABUTMENT ;
    PORT
      LAYER M3 ;
      RECT 122.355 0.000 122.373 0.054 ;
    END
  END rw0_rd_out[53]
  PIN rw0_rd_out[54]
    DIRECTION OUTPUT ;
    USE SIGNAL ;
    SHAPE ABUTMENT ;
    PORT
      LAYER M3 ;
      RECT 123.399 0.000 123.417 0.054 ;
    END
  END rw0_rd_out[54]
  PIN rw0_rd_out[55]
    DIRECTION OUTPUT ;
    USE SIGNAL ;
    SHAPE ABUTMENT ;
    PORT
      LAYER M3 ;
      RECT 124.443 0.000 124.461 0.054 ;
    END
  END rw0_rd_out[55]
  PIN rw0_rd_out[56]
    DIRECTION OUTPUT ;
    USE SIGNAL ;
    SHAPE ABUTMENT ;
    PORT
      LAYER M3 ;
      RECT 125.487 0.000 125.505 0.054 ;
    END
  END rw0_rd_out[56]
  PIN rw0_rd_out[57]
    DIRECTION OUTPUT ;
    USE SIGNAL ;
    SHAPE ABUTMENT ;
    PORT
      LAYER M3 ;
      RECT 126.531 0.000 126.549 0.054 ;
    END
  END rw0_rd_out[57]
  PIN rw0_rd_out[58]
    DIRECTION OUTPUT ;
    USE SIGNAL ;
    SHAPE ABUTMENT ;
    PORT
      LAYER M3 ;
      RECT 127.575 0.000 127.593 0.054 ;
    END
  END rw0_rd_out[58]
  PIN rw0_rd_out[59]
    DIRECTION OUTPUT ;
    USE SIGNAL ;
    SHAPE ABUTMENT ;
    PORT
      LAYER M3 ;
      RECT 128.619 0.000 128.637 0.054 ;
    END
  END rw0_rd_out[59]
  PIN rw0_rd_out[60]
    DIRECTION OUTPUT ;
    USE SIGNAL ;
    SHAPE ABUTMENT ;
    PORT
      LAYER M3 ;
      RECT 129.663 0.000 129.681 0.054 ;
    END
  END rw0_rd_out[60]
  PIN rw0_rd_out[61]
    DIRECTION OUTPUT ;
    USE SIGNAL ;
    SHAPE ABUTMENT ;
    PORT
      LAYER M3 ;
      RECT 130.707 0.000 130.725 0.054 ;
    END
  END rw0_rd_out[61]
  PIN rw0_rd_out[62]
    DIRECTION OUTPUT ;
    USE SIGNAL ;
    SHAPE ABUTMENT ;
    PORT
      LAYER M3 ;
      RECT 131.751 0.000 131.769 0.054 ;
    END
  END rw0_rd_out[62]
  PIN rw0_rd_out[63]
    DIRECTION OUTPUT ;
    USE SIGNAL ;
    SHAPE ABUTMENT ;
    PORT
      LAYER M3 ;
      RECT 132.795 0.000 132.813 0.054 ;
    END
  END rw0_rd_out[63]
  PIN rw0_rd_out[64]
    DIRECTION OUTPUT ;
    USE SIGNAL ;
    SHAPE ABUTMENT ;
    PORT
      LAYER M3 ;
      RECT 0.207 86.746 0.225 86.800 ;
    END
  END rw0_rd_out[64]
  PIN rw0_rd_out[65]
    DIRECTION OUTPUT ;
    USE SIGNAL ;
    SHAPE ABUTMENT ;
    PORT
      LAYER M3 ;
      RECT 2.259 86.746 2.277 86.800 ;
    END
  END rw0_rd_out[65]
  PIN rw0_rd_out[66]
    DIRECTION OUTPUT ;
    USE SIGNAL ;
    SHAPE ABUTMENT ;
    PORT
      LAYER M3 ;
      RECT 4.311 86.746 4.329 86.800 ;
    END
  END rw0_rd_out[66]
  PIN rw0_rd_out[67]
    DIRECTION OUTPUT ;
    USE SIGNAL ;
    SHAPE ABUTMENT ;
    PORT
      LAYER M3 ;
      RECT 6.363 86.746 6.381 86.800 ;
    END
  END rw0_rd_out[67]
  PIN rw0_rd_out[68]
    DIRECTION OUTPUT ;
    USE SIGNAL ;
    SHAPE ABUTMENT ;
    PORT
      LAYER M3 ;
      RECT 8.415 86.746 8.433 86.800 ;
    END
  END rw0_rd_out[68]
  PIN rw0_rd_out[69]
    DIRECTION OUTPUT ;
    USE SIGNAL ;
    SHAPE ABUTMENT ;
    PORT
      LAYER M3 ;
      RECT 10.467 86.746 10.485 86.800 ;
    END
  END rw0_rd_out[69]
  PIN rw0_rd_out[70]
    DIRECTION OUTPUT ;
    USE SIGNAL ;
    SHAPE ABUTMENT ;
    PORT
      LAYER M3 ;
      RECT 12.519 86.746 12.537 86.800 ;
    END
  END rw0_rd_out[70]
  PIN rw0_rd_out[71]
    DIRECTION OUTPUT ;
    USE SIGNAL ;
    SHAPE ABUTMENT ;
    PORT
      LAYER M3 ;
      RECT 14.571 86.746 14.589 86.800 ;
    END
  END rw0_rd_out[71]
  PIN rw0_rd_out[72]
    DIRECTION OUTPUT ;
    USE SIGNAL ;
    SHAPE ABUTMENT ;
    PORT
      LAYER M3 ;
      RECT 16.623 86.746 16.641 86.800 ;
    END
  END rw0_rd_out[72]
  PIN rw0_rd_out[73]
    DIRECTION OUTPUT ;
    USE SIGNAL ;
    SHAPE ABUTMENT ;
    PORT
      LAYER M3 ;
      RECT 18.675 86.746 18.693 86.800 ;
    END
  END rw0_rd_out[73]
  PIN rw0_rd_out[74]
    DIRECTION OUTPUT ;
    USE SIGNAL ;
    SHAPE ABUTMENT ;
    PORT
      LAYER M3 ;
      RECT 20.727 86.746 20.745 86.800 ;
    END
  END rw0_rd_out[74]
  PIN rw0_rd_out[75]
    DIRECTION OUTPUT ;
    USE SIGNAL ;
    SHAPE ABUTMENT ;
    PORT
      LAYER M3 ;
      RECT 22.779 86.746 22.797 86.800 ;
    END
  END rw0_rd_out[75]
  PIN rw0_rd_out[76]
    DIRECTION OUTPUT ;
    USE SIGNAL ;
    SHAPE ABUTMENT ;
    PORT
      LAYER M3 ;
      RECT 24.831 86.746 24.849 86.800 ;
    END
  END rw0_rd_out[76]
  PIN rw0_rd_out[77]
    DIRECTION OUTPUT ;
    USE SIGNAL ;
    SHAPE ABUTMENT ;
    PORT
      LAYER M3 ;
      RECT 26.883 86.746 26.901 86.800 ;
    END
  END rw0_rd_out[77]
  PIN rw0_rd_out[78]
    DIRECTION OUTPUT ;
    USE SIGNAL ;
    SHAPE ABUTMENT ;
    PORT
      LAYER M3 ;
      RECT 28.935 86.746 28.953 86.800 ;
    END
  END rw0_rd_out[78]
  PIN rw0_rd_out[79]
    DIRECTION OUTPUT ;
    USE SIGNAL ;
    SHAPE ABUTMENT ;
    PORT
      LAYER M3 ;
      RECT 30.987 86.746 31.005 86.800 ;
    END
  END rw0_rd_out[79]
  PIN rw0_rd_out[80]
    DIRECTION OUTPUT ;
    USE SIGNAL ;
    SHAPE ABUTMENT ;
    PORT
      LAYER M3 ;
      RECT 33.039 86.746 33.057 86.800 ;
    END
  END rw0_rd_out[80]
  PIN rw0_rd_out[81]
    DIRECTION OUTPUT ;
    USE SIGNAL ;
    SHAPE ABUTMENT ;
    PORT
      LAYER M3 ;
      RECT 35.091 86.746 35.109 86.800 ;
    END
  END rw0_rd_out[81]
  PIN rw0_rd_out[82]
    DIRECTION OUTPUT ;
    USE SIGNAL ;
    SHAPE ABUTMENT ;
    PORT
      LAYER M3 ;
      RECT 37.143 86.746 37.161 86.800 ;
    END
  END rw0_rd_out[82]
  PIN rw0_rd_out[83]
    DIRECTION OUTPUT ;
    USE SIGNAL ;
    SHAPE ABUTMENT ;
    PORT
      LAYER M3 ;
      RECT 39.195 86.746 39.213 86.800 ;
    END
  END rw0_rd_out[83]
  PIN rw0_rd_out[84]
    DIRECTION OUTPUT ;
    USE SIGNAL ;
    SHAPE ABUTMENT ;
    PORT
      LAYER M3 ;
      RECT 41.247 86.746 41.265 86.800 ;
    END
  END rw0_rd_out[84]
  PIN rw0_rd_out[85]
    DIRECTION OUTPUT ;
    USE SIGNAL ;
    SHAPE ABUTMENT ;
    PORT
      LAYER M3 ;
      RECT 43.299 86.746 43.317 86.800 ;
    END
  END rw0_rd_out[85]
  PIN rw0_rd_out[86]
    DIRECTION OUTPUT ;
    USE SIGNAL ;
    SHAPE ABUTMENT ;
    PORT
      LAYER M3 ;
      RECT 45.351 86.746 45.369 86.800 ;
    END
  END rw0_rd_out[86]
  PIN rw0_rd_out[87]
    DIRECTION OUTPUT ;
    USE SIGNAL ;
    SHAPE ABUTMENT ;
    PORT
      LAYER M3 ;
      RECT 47.403 86.746 47.421 86.800 ;
    END
  END rw0_rd_out[87]
  PIN rw0_rd_out[88]
    DIRECTION OUTPUT ;
    USE SIGNAL ;
    SHAPE ABUTMENT ;
    PORT
      LAYER M3 ;
      RECT 49.455 86.746 49.473 86.800 ;
    END
  END rw0_rd_out[88]
  PIN rw0_rd_out[89]
    DIRECTION OUTPUT ;
    USE SIGNAL ;
    SHAPE ABUTMENT ;
    PORT
      LAYER M3 ;
      RECT 51.507 86.746 51.525 86.800 ;
    END
  END rw0_rd_out[89]
  PIN rw0_rd_out[90]
    DIRECTION OUTPUT ;
    USE SIGNAL ;
    SHAPE ABUTMENT ;
    PORT
      LAYER M3 ;
      RECT 53.559 86.746 53.577 86.800 ;
    END
  END rw0_rd_out[90]
  PIN rw0_rd_out[91]
    DIRECTION OUTPUT ;
    USE SIGNAL ;
    SHAPE ABUTMENT ;
    PORT
      LAYER M3 ;
      RECT 55.611 86.746 55.629 86.800 ;
    END
  END rw0_rd_out[91]
  PIN rw0_rd_out[92]
    DIRECTION OUTPUT ;
    USE SIGNAL ;
    SHAPE ABUTMENT ;
    PORT
      LAYER M3 ;
      RECT 57.663 86.746 57.681 86.800 ;
    END
  END rw0_rd_out[92]
  PIN rw0_rd_out[93]
    DIRECTION OUTPUT ;
    USE SIGNAL ;
    SHAPE ABUTMENT ;
    PORT
      LAYER M3 ;
      RECT 59.715 86.746 59.733 86.800 ;
    END
  END rw0_rd_out[93]
  PIN rw0_rd_out[94]
    DIRECTION OUTPUT ;
    USE SIGNAL ;
    SHAPE ABUTMENT ;
    PORT
      LAYER M3 ;
      RECT 61.767 86.746 61.785 86.800 ;
    END
  END rw0_rd_out[94]
  PIN rw0_rd_out[95]
    DIRECTION OUTPUT ;
    USE SIGNAL ;
    SHAPE ABUTMENT ;
    PORT
      LAYER M3 ;
      RECT 63.819 86.746 63.837 86.800 ;
    END
  END rw0_rd_out[95]
  PIN rw0_rd_out[96]
    DIRECTION OUTPUT ;
    USE SIGNAL ;
    SHAPE ABUTMENT ;
    PORT
      LAYER M3 ;
      RECT 65.871 86.746 65.889 86.800 ;
    END
  END rw0_rd_out[96]
  PIN rw0_rd_out[97]
    DIRECTION OUTPUT ;
    USE SIGNAL ;
    SHAPE ABUTMENT ;
    PORT
      LAYER M3 ;
      RECT 67.923 86.746 67.941 86.800 ;
    END
  END rw0_rd_out[97]
  PIN rw0_rd_out[98]
    DIRECTION OUTPUT ;
    USE SIGNAL ;
    SHAPE ABUTMENT ;
    PORT
      LAYER M3 ;
      RECT 69.975 86.746 69.993 86.800 ;
    END
  END rw0_rd_out[98]
  PIN rw0_rd_out[99]
    DIRECTION OUTPUT ;
    USE SIGNAL ;
    SHAPE ABUTMENT ;
    PORT
      LAYER M3 ;
      RECT 72.027 86.746 72.045 86.800 ;
    END
  END rw0_rd_out[99]
  PIN rw0_rd_out[100]
    DIRECTION OUTPUT ;
    USE SIGNAL ;
    SHAPE ABUTMENT ;
    PORT
      LAYER M3 ;
      RECT 74.079 86.746 74.097 86.800 ;
    END
  END rw0_rd_out[100]
  PIN rw0_rd_out[101]
    DIRECTION OUTPUT ;
    USE SIGNAL ;
    SHAPE ABUTMENT ;
    PORT
      LAYER M3 ;
      RECT 76.131 86.746 76.149 86.800 ;
    END
  END rw0_rd_out[101]
  PIN rw0_rd_out[102]
    DIRECTION OUTPUT ;
    USE SIGNAL ;
    SHAPE ABUTMENT ;
    PORT
      LAYER M3 ;
      RECT 78.183 86.746 78.201 86.800 ;
    END
  END rw0_rd_out[102]
  PIN rw0_rd_out[103]
    DIRECTION OUTPUT ;
    USE SIGNAL ;
    SHAPE ABUTMENT ;
    PORT
      LAYER M3 ;
      RECT 80.235 86.746 80.253 86.800 ;
    END
  END rw0_rd_out[103]
  PIN rw0_rd_out[104]
    DIRECTION OUTPUT ;
    USE SIGNAL ;
    SHAPE ABUTMENT ;
    PORT
      LAYER M3 ;
      RECT 82.287 86.746 82.305 86.800 ;
    END
  END rw0_rd_out[104]
  PIN rw0_rd_out[105]
    DIRECTION OUTPUT ;
    USE SIGNAL ;
    SHAPE ABUTMENT ;
    PORT
      LAYER M3 ;
      RECT 84.339 86.746 84.357 86.800 ;
    END
  END rw0_rd_out[105]
  PIN rw0_rd_out[106]
    DIRECTION OUTPUT ;
    USE SIGNAL ;
    SHAPE ABUTMENT ;
    PORT
      LAYER M3 ;
      RECT 86.391 86.746 86.409 86.800 ;
    END
  END rw0_rd_out[106]
  PIN rw0_rd_out[107]
    DIRECTION OUTPUT ;
    USE SIGNAL ;
    SHAPE ABUTMENT ;
    PORT
      LAYER M3 ;
      RECT 88.443 86.746 88.461 86.800 ;
    END
  END rw0_rd_out[107]
  PIN rw0_rd_out[108]
    DIRECTION OUTPUT ;
    USE SIGNAL ;
    SHAPE ABUTMENT ;
    PORT
      LAYER M3 ;
      RECT 90.495 86.746 90.513 86.800 ;
    END
  END rw0_rd_out[108]
  PIN rw0_rd_out[109]
    DIRECTION OUTPUT ;
    USE SIGNAL ;
    SHAPE ABUTMENT ;
    PORT
      LAYER M3 ;
      RECT 92.547 86.746 92.565 86.800 ;
    END
  END rw0_rd_out[109]
  PIN rw0_rd_out[110]
    DIRECTION OUTPUT ;
    USE SIGNAL ;
    SHAPE ABUTMENT ;
    PORT
      LAYER M3 ;
      RECT 94.599 86.746 94.617 86.800 ;
    END
  END rw0_rd_out[110]
  PIN rw0_rd_out[111]
    DIRECTION OUTPUT ;
    USE SIGNAL ;
    SHAPE ABUTMENT ;
    PORT
      LAYER M3 ;
      RECT 96.651 86.746 96.669 86.800 ;
    END
  END rw0_rd_out[111]
  PIN rw0_rd_out[112]
    DIRECTION OUTPUT ;
    USE SIGNAL ;
    SHAPE ABUTMENT ;
    PORT
      LAYER M3 ;
      RECT 98.703 86.746 98.721 86.800 ;
    END
  END rw0_rd_out[112]
  PIN rw0_rd_out[113]
    DIRECTION OUTPUT ;
    USE SIGNAL ;
    SHAPE ABUTMENT ;
    PORT
      LAYER M3 ;
      RECT 100.755 86.746 100.773 86.800 ;
    END
  END rw0_rd_out[113]
  PIN rw0_rd_out[114]
    DIRECTION OUTPUT ;
    USE SIGNAL ;
    SHAPE ABUTMENT ;
    PORT
      LAYER M3 ;
      RECT 102.807 86.746 102.825 86.800 ;
    END
  END rw0_rd_out[114]
  PIN rw0_rd_out[115]
    DIRECTION OUTPUT ;
    USE SIGNAL ;
    SHAPE ABUTMENT ;
    PORT
      LAYER M3 ;
      RECT 104.859 86.746 104.877 86.800 ;
    END
  END rw0_rd_out[115]
  PIN rw0_rd_out[116]
    DIRECTION OUTPUT ;
    USE SIGNAL ;
    SHAPE ABUTMENT ;
    PORT
      LAYER M3 ;
      RECT 106.911 86.746 106.929 86.800 ;
    END
  END rw0_rd_out[116]
  PIN rw0_rd_out[117]
    DIRECTION OUTPUT ;
    USE SIGNAL ;
    SHAPE ABUTMENT ;
    PORT
      LAYER M3 ;
      RECT 108.963 86.746 108.981 86.800 ;
    END
  END rw0_rd_out[117]
  PIN rw0_rd_out[118]
    DIRECTION OUTPUT ;
    USE SIGNAL ;
    SHAPE ABUTMENT ;
    PORT
      LAYER M3 ;
      RECT 111.015 86.746 111.033 86.800 ;
    END
  END rw0_rd_out[118]
  PIN rw0_rd_out[119]
    DIRECTION OUTPUT ;
    USE SIGNAL ;
    SHAPE ABUTMENT ;
    PORT
      LAYER M3 ;
      RECT 113.067 86.746 113.085 86.800 ;
    END
  END rw0_rd_out[119]
  PIN rw0_rd_out[120]
    DIRECTION OUTPUT ;
    USE SIGNAL ;
    SHAPE ABUTMENT ;
    PORT
      LAYER M3 ;
      RECT 115.119 86.746 115.137 86.800 ;
    END
  END rw0_rd_out[120]
  PIN rw0_rd_out[121]
    DIRECTION OUTPUT ;
    USE SIGNAL ;
    SHAPE ABUTMENT ;
    PORT
      LAYER M3 ;
      RECT 117.171 86.746 117.189 86.800 ;
    END
  END rw0_rd_out[121]
  PIN rw0_rd_out[122]
    DIRECTION OUTPUT ;
    USE SIGNAL ;
    SHAPE ABUTMENT ;
    PORT
      LAYER M3 ;
      RECT 119.223 86.746 119.241 86.800 ;
    END
  END rw0_rd_out[122]
  PIN rw0_rd_out[123]
    DIRECTION OUTPUT ;
    USE SIGNAL ;
    SHAPE ABUTMENT ;
    PORT
      LAYER M3 ;
      RECT 121.275 86.746 121.293 86.800 ;
    END
  END rw0_rd_out[123]
  PIN rw0_rd_out[124]
    DIRECTION OUTPUT ;
    USE SIGNAL ;
    SHAPE ABUTMENT ;
    PORT
      LAYER M3 ;
      RECT 123.327 86.746 123.345 86.800 ;
    END
  END rw0_rd_out[124]
  PIN rw0_rd_out[125]
    DIRECTION OUTPUT ;
    USE SIGNAL ;
    SHAPE ABUTMENT ;
    PORT
      LAYER M3 ;
      RECT 125.379 86.746 125.397 86.800 ;
    END
  END rw0_rd_out[125]
  PIN rw0_rd_out[126]
    DIRECTION OUTPUT ;
    USE SIGNAL ;
    SHAPE ABUTMENT ;
    PORT
      LAYER M3 ;
      RECT 127.431 86.746 127.449 86.800 ;
    END
  END rw0_rd_out[126]
  PIN rw0_rd_out[127]
    DIRECTION OUTPUT ;
    USE SIGNAL ;
    SHAPE ABUTMENT ;
    PORT
      LAYER M3 ;
      RECT 129.483 86.746 129.501 86.800 ;
    END
  END rw0_rd_out[127]
  PIN rw0_addr_in[0]
    DIRECTION INPUT ;
    USE SIGNAL ;
    SHAPE ABUTMENT ;
    PORT
      LAYER M4 ;
      RECT 0.000 74.004 0.072 74.028 ;
    END
  END rw0_addr_in[0]
  PIN rw0_addr_in[1]
    DIRECTION INPUT ;
    USE SIGNAL ;
    SHAPE ABUTMENT ;
    PORT
      LAYER M4 ;
      RECT 0.000 76.308 0.072 76.332 ;
    END
  END rw0_addr_in[1]
  PIN rw0_addr_in[2]
    DIRECTION INPUT ;
    USE SIGNAL ;
    SHAPE ABUTMENT ;
    PORT
      LAYER M4 ;
      RECT 0.000 78.612 0.072 78.636 ;
    END
  END rw0_addr_in[2]
  PIN rw0_addr_in[3]
    DIRECTION INPUT ;
    USE SIGNAL ;
    SHAPE ABUTMENT ;
    PORT
      LAYER M4 ;
      RECT 0.000 80.916 0.072 80.940 ;
    END
  END rw0_addr_in[3]
  PIN rw0_addr_in[4]
    DIRECTION INPUT ;
    USE SIGNAL ;
    SHAPE ABUTMENT ;
    PORT
      LAYER M4 ;
      RECT 0.000 83.220 0.072 83.244 ;
    END
  END rw0_addr_in[4]
  PIN rw0_addr_in[5]
    DIRECTION INPUT ;
    USE SIGNAL ;
    SHAPE ABUTMENT ;
    PORT
      LAYER M4 ;
      RECT 138.248 74.004 138.320 74.028 ;
    END
  END rw0_addr_in[5]
  PIN rw0_addr_in[6]
    DIRECTION INPUT ;
    USE SIGNAL ;
    SHAPE ABUTMENT ;
    PORT
      LAYER M4 ;
      RECT 138.248 76.308 138.320 76.332 ;
    END
  END rw0_addr_in[6]
  PIN rw0_addr_in[7]
    DIRECTION INPUT ;
    USE SIGNAL ;
    SHAPE ABUTMENT ;
    PORT
      LAYER M4 ;
      RECT 138.248 78.612 138.320 78.636 ;
    END
  END rw0_addr_in[7]
  PIN rw0_addr_in[8]
    DIRECTION INPUT ;
    USE SIGNAL ;
    SHAPE ABUTMENT ;
    PORT
      LAYER M4 ;
      RECT 138.248 80.916 138.320 80.940 ;
    END
  END rw0_addr_in[8]
  PIN rw0_we_in
    DIRECTION INPUT ;
    USE SIGNAL ;
    SHAPE ABUTMENT ;
    PORT
      LAYER M3 ;
      RECT 131.535 86.746 131.553 86.800 ;
    END
  END rw0_we_in
  PIN rw0_ce_in
    DIRECTION INPUT ;
    USE SIGNAL ;
    SHAPE ABUTMENT ;
    PORT
      LAYER M3 ;
      RECT 133.587 86.746 133.605 86.800 ;
    END
  END rw0_ce_in
  PIN rw0_clk
    DIRECTION INPUT ;
    USE SIGNAL ;
    SHAPE ABUTMENT ;
    PORT
      LAYER M3 ;
      RECT 135.639 86.746 135.657 86.800 ;
    END
  END rw0_clk
  PIN VSS
    DIRECTION INOUT ;
    USE GROUND ;
    PORT
      LAYER M4 ;
      RECT 0.216 0.240 138.104 0.336 ;
      RECT 0.216 1.008 138.104 1.104 ;
      RECT 0.216 1.776 138.104 1.872 ;
      RECT 0.216 2.544 138.104 2.640 ;
      RECT 0.216 3.312 138.104 3.408 ;
      RECT 0.216 4.080 138.104 4.176 ;
      RECT 0.216 4.848 138.104 4.944 ;
      RECT 0.216 5.616 138.104 5.712 ;
      RECT 0.216 6.384 138.104 6.480 ;
      RECT 0.216 7.152 138.104 7.248 ;
      RECT 0.216 7.920 138.104 8.016 ;
      RECT 0.216 8.688 138.104 8.784 ;
      RECT 0.216 9.456 138.104 9.552 ;
      RECT 0.216 10.224 138.104 10.320 ;
      RECT 0.216 10.992 138.104 11.088 ;
      RECT 0.216 11.760 138.104 11.856 ;
      RECT 0.216 12.528 138.104 12.624 ;
      RECT 0.216 13.296 138.104 13.392 ;
      RECT 0.216 14.064 138.104 14.160 ;
      RECT 0.216 14.832 138.104 14.928 ;
      RECT 0.216 15.600 138.104 15.696 ;
      RECT 0.216 16.368 138.104 16.464 ;
      RECT 0.216 17.136 138.104 17.232 ;
      RECT 0.216 17.904 138.104 18.000 ;
      RECT 0.216 18.672 138.104 18.768 ;
      RECT 0.216 19.440 138.104 19.536 ;
      RECT 0.216 20.208 138.104 20.304 ;
      RECT 0.216 20.976 138.104 21.072 ;
      RECT 0.216 21.744 138.104 21.840 ;
      RECT 0.216 22.512 138.104 22.608 ;
      RECT 0.216 23.280 138.104 23.376 ;
      RECT 0.216 24.048 138.104 24.144 ;
      RECT 0.216 24.816 138.104 24.912 ;
      RECT 0.216 25.584 138.104 25.680 ;
      RECT 0.216 26.352 138.104 26.448 ;
      RECT 0.216 27.120 138.104 27.216 ;
      RECT 0.216 27.888 138.104 27.984 ;
      RECT 0.216 28.656 138.104 28.752 ;
      RECT 0.216 29.424 138.104 29.520 ;
      RECT 0.216 30.192 138.104 30.288 ;
      RECT 0.216 30.960 138.104 31.056 ;
      RECT 0.216 31.728 138.104 31.824 ;
      RECT 0.216 32.496 138.104 32.592 ;
      RECT 0.216 33.264 138.104 33.360 ;
      RECT 0.216 34.032 138.104 34.128 ;
      RECT 0.216 34.800 138.104 34.896 ;
      RECT 0.216 35.568 138.104 35.664 ;
      RECT 0.216 36.336 138.104 36.432 ;
      RECT 0.216 37.104 138.104 37.200 ;
      RECT 0.216 37.872 138.104 37.968 ;
      RECT 0.216 38.640 138.104 38.736 ;
      RECT 0.216 39.408 138.104 39.504 ;
      RECT 0.216 40.176 138.104 40.272 ;
      RECT 0.216 40.944 138.104 41.040 ;
      RECT 0.216 41.712 138.104 41.808 ;
      RECT 0.216 42.480 138.104 42.576 ;
      RECT 0.216 43.248 138.104 43.344 ;
      RECT 0.216 44.016 138.104 44.112 ;
      RECT 0.216 44.784 138.104 44.880 ;
      RECT 0.216 45.552 138.104 45.648 ;
      RECT 0.216 46.320 138.104 46.416 ;
      RECT 0.216 47.088 138.104 47.184 ;
      RECT 0.216 47.856 138.104 47.952 ;
      RECT 0.216 48.624 138.104 48.720 ;
      RECT 0.216 49.392 138.104 49.488 ;
      RECT 0.216 50.160 138.104 50.256 ;
      RECT 0.216 50.928 138.104 51.024 ;
      RECT 0.216 51.696 138.104 51.792 ;
      RECT 0.216 52.464 138.104 52.560 ;
      RECT 0.216 53.232 138.104 53.328 ;
      RECT 0.216 54.000 138.104 54.096 ;
      RECT 0.216 54.768 138.104 54.864 ;
      RECT 0.216 55.536 138.104 55.632 ;
      RECT 0.216 56.304 138.104 56.400 ;
      RECT 0.216 57.072 138.104 57.168 ;
      RECT 0.216 57.840 138.104 57.936 ;
      RECT 0.216 58.608 138.104 58.704 ;
      RECT 0.216 59.376 138.104 59.472 ;
      RECT 0.216 60.144 138.104 60.240 ;
      RECT 0.216 60.912 138.104 61.008 ;
      RECT 0.216 61.680 138.104 61.776 ;
      RECT 0.216 62.448 138.104 62.544 ;
      RECT 0.216 63.216 138.104 63.312 ;
      RECT 0.216 63.984 138.104 64.080 ;
      RECT 0.216 64.752 138.104 64.848 ;
      RECT 0.216 65.520 138.104 65.616 ;
      RECT 0.216 66.288 138.104 66.384 ;
      RECT 0.216 67.056 138.104 67.152 ;
      RECT 0.216 67.824 138.104 67.920 ;
      RECT 0.216 68.592 138.104 68.688 ;
      RECT 0.216 69.360 138.104 69.456 ;
      RECT 0.216 70.128 138.104 70.224 ;
      RECT 0.216 70.896 138.104 70.992 ;
      RECT 0.216 71.664 138.104 71.760 ;
      RECT 0.216 72.432 138.104 72.528 ;
      RECT 0.216 73.200 138.104 73.296 ;
      RECT 0.216 73.968 138.104 74.064 ;
      RECT 0.216 74.736 138.104 74.832 ;
      RECT 0.216 75.504 138.104 75.600 ;
      RECT 0.216 76.272 138.104 76.368 ;
      RECT 0.216 77.040 138.104 77.136 ;
      RECT 0.216 77.808 138.104 77.904 ;
      RECT 0.216 78.576 138.104 78.672 ;
      RECT 0.216 79.344 138.104 79.440 ;
      RECT 0.216 80.112 138.104 80.208 ;
      RECT 0.216 80.880 138.104 80.976 ;
      RECT 0.216 81.648 138.104 81.744 ;
      RECT 0.216 82.416 138.104 82.512 ;
      RECT 0.216 83.184 138.104 83.280 ;
      RECT 0.216 83.952 138.104 84.048 ;
      RECT 0.216 84.720 138.104 84.816 ;
      RECT 0.216 85.488 138.104 85.584 ;
      RECT 0.216 86.256 138.104 86.352 ;
    END
  END VSS
  PIN VDD
    DIRECTION INOUT ;
    USE POWER ;
    PORT
      LAYER M4 ;
      RECT 0.216 0.624 138.104 0.720 ;
      RECT 0.216 1.392 138.104 1.488 ;
      RECT 0.216 2.160 138.104 2.256 ;
      RECT 0.216 2.928 138.104 3.024 ;
      RECT 0.216 3.696 138.104 3.792 ;
      RECT 0.216 4.464 138.104 4.560 ;
      RECT 0.216 5.232 138.104 5.328 ;
      RECT 0.216 6.000 138.104 6.096 ;
      RECT 0.216 6.768 138.104 6.864 ;
      RECT 0.216 7.536 138.104 7.632 ;
      RECT 0.216 8.304 138.104 8.400 ;
      RECT 0.216 9.072 138.104 9.168 ;
      RECT 0.216 9.840 138.104 9.936 ;
      RECT 0.216 10.608 138.104 10.704 ;
      RECT 0.216 11.376 138.104 11.472 ;
      RECT 0.216 12.144 138.104 12.240 ;
      RECT 0.216 12.912 138.104 13.008 ;
      RECT 0.216 13.680 138.104 13.776 ;
      RECT 0.216 14.448 138.104 14.544 ;
      RECT 0.216 15.216 138.104 15.312 ;
      RECT 0.216 15.984 138.104 16.080 ;
      RECT 0.216 16.752 138.104 16.848 ;
      RECT 0.216 17.520 138.104 17.616 ;
      RECT 0.216 18.288 138.104 18.384 ;
      RECT 0.216 19.056 138.104 19.152 ;
      RECT 0.216 19.824 138.104 19.920 ;
      RECT 0.216 20.592 138.104 20.688 ;
      RECT 0.216 21.360 138.104 21.456 ;
      RECT 0.216 22.128 138.104 22.224 ;
      RECT 0.216 22.896 138.104 22.992 ;
      RECT 0.216 23.664 138.104 23.760 ;
      RECT 0.216 24.432 138.104 24.528 ;
      RECT 0.216 25.200 138.104 25.296 ;
      RECT 0.216 25.968 138.104 26.064 ;
      RECT 0.216 26.736 138.104 26.832 ;
      RECT 0.216 27.504 138.104 27.600 ;
      RECT 0.216 28.272 138.104 28.368 ;
      RECT 0.216 29.040 138.104 29.136 ;
      RECT 0.216 29.808 138.104 29.904 ;
      RECT 0.216 30.576 138.104 30.672 ;
      RECT 0.216 31.344 138.104 31.440 ;
      RECT 0.216 32.112 138.104 32.208 ;
      RECT 0.216 32.880 138.104 32.976 ;
      RECT 0.216 33.648 138.104 33.744 ;
      RECT 0.216 34.416 138.104 34.512 ;
      RECT 0.216 35.184 138.104 35.280 ;
      RECT 0.216 35.952 138.104 36.048 ;
      RECT 0.216 36.720 138.104 36.816 ;
      RECT 0.216 37.488 138.104 37.584 ;
      RECT 0.216 38.256 138.104 38.352 ;
      RECT 0.216 39.024 138.104 39.120 ;
      RECT 0.216 39.792 138.104 39.888 ;
      RECT 0.216 40.560 138.104 40.656 ;
      RECT 0.216 41.328 138.104 41.424 ;
      RECT 0.216 42.096 138.104 42.192 ;
      RECT 0.216 42.864 138.104 42.960 ;
      RECT 0.216 43.632 138.104 43.728 ;
      RECT 0.216 44.400 138.104 44.496 ;
      RECT 0.216 45.168 138.104 45.264 ;
      RECT 0.216 45.936 138.104 46.032 ;
      RECT 0.216 46.704 138.104 46.800 ;
      RECT 0.216 47.472 138.104 47.568 ;
      RECT 0.216 48.240 138.104 48.336 ;
      RECT 0.216 49.008 138.104 49.104 ;
      RECT 0.216 49.776 138.104 49.872 ;
      RECT 0.216 50.544 138.104 50.640 ;
      RECT 0.216 51.312 138.104 51.408 ;
      RECT 0.216 52.080 138.104 52.176 ;
      RECT 0.216 52.848 138.104 52.944 ;
      RECT 0.216 53.616 138.104 53.712 ;
      RECT 0.216 54.384 138.104 54.480 ;
      RECT 0.216 55.152 138.104 55.248 ;
      RECT 0.216 55.920 138.104 56.016 ;
      RECT 0.216 56.688 138.104 56.784 ;
      RECT 0.216 57.456 138.104 57.552 ;
      RECT 0.216 58.224 138.104 58.320 ;
      RECT 0.216 58.992 138.104 59.088 ;
      RECT 0.216 59.760 138.104 59.856 ;
      RECT 0.216 60.528 138.104 60.624 ;
      RECT 0.216 61.296 138.104 61.392 ;
      RECT 0.216 62.064 138.104 62.160 ;
      RECT 0.216 62.832 138.104 62.928 ;
      RECT 0.216 63.600 138.104 63.696 ;
      RECT 0.216 64.368 138.104 64.464 ;
      RECT 0.216 65.136 138.104 65.232 ;
      RECT 0.216 65.904 138.104 66.000 ;
      RECT 0.216 66.672 138.104 66.768 ;
      RECT 0.216 67.440 138.104 67.536 ;
      RECT 0.216 68.208 138.104 68.304 ;
      RECT 0.216 68.976 138.104 69.072 ;
      RECT 0.216 69.744 138.104 69.840 ;
      RECT 0.216 70.512 138.104 70.608 ;
      RECT 0.216 71.280 138.104 71.376 ;
      RECT 0.216 72.048 138.104 72.144 ;
      RECT 0.216 72.816 138.104 72.912 ;
      RECT 0.216 73.584 138.104 73.680 ;
      RECT 0.216 74.352 138.104 74.448 ;
      RECT 0.216 75.120 138.104 75.216 ;
      RECT 0.216 75.888 138.104 75.984 ;
      RECT 0.216 76.656 138.104 76.752 ;
      RECT 0.216 77.424 138.104 77.520 ;
      RECT 0.216 78.192 138.104 78.288 ;
      RECT 0.216 78.960 138.104 79.056 ;
      RECT 0.216 79.728 138.104 79.824 ;
      RECT 0.216 80.496 138.104 80.592 ;
      RECT 0.216 81.264 138.104 81.360 ;
      RECT 0.216 82.032 138.104 82.128 ;
      RECT 0.216 82.800 138.104 82.896 ;
      RECT 0.216 83.568 138.104 83.664 ;
      RECT 0.216 84.336 138.104 84.432 ;
      RECT 0.216 85.104 138.104 85.200 ;
      RECT 0.216 85.872 138.104 85.968 ;
      RECT 0.216 86.640 138.104 86.736 ;
    END
  END VDD
  OBS
    LAYER M1 ;
    RECT 0 0 138.320 86.800 ;
    LAYER M2 ;
    RECT 0 0 138.320 86.800 ;
    LAYER M3 ;
    RECT 0 0 138.320 86.800 ;
    LAYER M4 ;
    RECT 0 0 138.320 86.800 ;
  END
END fakeram_512x128

END LIBRARY
